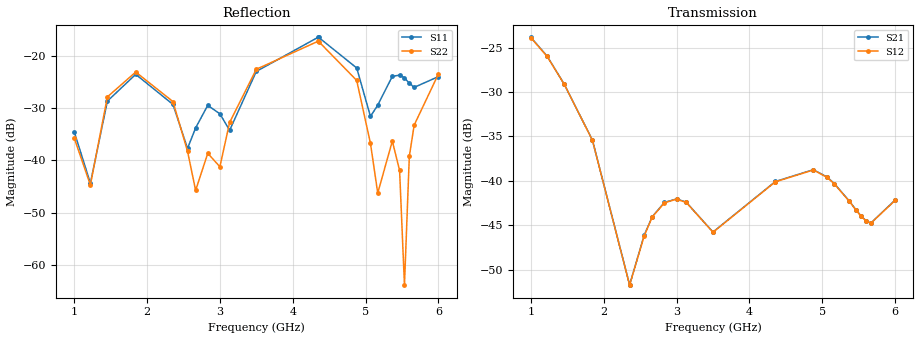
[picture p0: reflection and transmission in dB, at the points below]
!Agilent Technologies,E8364B,MY43040528,A.07.50.67
!Agilent E8364B: A.07.50.67
!Date: Sunday, March 01, 2026 22:24:54
!Correction: S11(Full 2 Port(1,2))
!S21(Full 2 Port(1,2))
!S12(Full 2 Port(1,2))
!S22(Full 2 Port(1,2))
!S2P File: Measurements: S11, S21, S12, S22:
# Hz S  dB  R 50
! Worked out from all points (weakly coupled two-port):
!   451 points, 1 GHz to 6 GHz, reference 50 ohm
!   highest |S21| = -23.85 dB at 1 GHz (marker M1); lowest = -51.7 dB at 2.356 GHz (marker M2)
!   lowest |S11| = -44.4 dB at 1.222 GHz (marker M3), VSWR 1.01, Z = 50.3 - j0.54 ohm
!   |S11| at or under -10 dB: start of sweep to end of sweep
!   |S22| runs from -63.8 to -17.2 dB; largest |S21 - S12| = 0.00025
!   S11 on the Smith chart (normalised r, x): 1 GHz: 1.04, +0.01; 4.356 GHz: 1.20, -0.26; 6 GHz: 0.96, -0.12
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1e9  -34.53 12.3  -23.85 155.1  -23.89 155.2  -35.72 -43.4
1.222222e9  -44.37 -62.7  -25.95 28.7  -25.99 28.7  -44.71 -159.7
1.455556e9  -28.68 172.1  -29.08 -100.9  -29.10 -100.8  -27.88 102.7
1.844444e9  -23.57 83.0  -35.40 51.9  -35.43 52.0  -23.13 -5.1
2.355556e9  -29.31 13.1  -51.72 -148.2  -51.75 -148.2  -28.78 -122.3
2.555556e9  -37.72 31.9  -46.13 157.8  -46.20 157.8  -38.26 169.8
2.666667e9  -33.81 67.3  -44.04 104.6  -44.07 104.7  -45.74 43.1
2.833333e9  -29.49 51.1  -42.44 19.2  -42.48 19.2  -38.66 -46.9
3e9  -31.12 31.2  -42.04 -68.1  -42.07 -68.1  -41.22 -34.8
3.133333e9  -34.26 56.4  -42.42 -137.6  -42.44 -137.6  -32.76 -19.1
3.5e9  -23.01 49.4  -45.77 47.7  -45.80 47.7  -22.60 -104.7
4.344444e9  -16.52 -44.2  -40.16 24.8  -40.19 24.8  -17.27 103.3
4.355556e9  -16.51 -45.9  -40.08 18.9  -40.12 18.9  -17.30 100.8
4.877778e9  -22.35 -131.2  -38.75 85.7  -38.78 85.8  -24.73 -28.3
5.066667e9  -31.61 -119.3  -39.58 -25.8  -39.62 -25.9  -36.76 -93.2
5.166667e9  -29.45 -77.8  -40.32 -86.2  -40.36 -86.2  -46.26 113.8
5.366667e9  -23.95 -91.8  -42.24 148.6  -42.27 148.7  -36.32 18.3
5.466667e9  -23.72 -105.8  -43.31 82.0  -43.34 82.0  -41.92 -19.5
5.533333e9  -24.27 -112.3  -43.96 35.5  -44.01 35.6  -63.84 2.3
5.6e9  -25.25 -116.9  -44.49 -12.4  -44.51 -12.4  -39.25 117.9
5.666667e9  -26.06 -116.4  -44.76 -61.6  -44.78 -61.6  -33.27 98.7
6e9  -24.00 -104.8  -42.17 61.4  -42.21 61.4  -23.49 3.0
